VERSION 5.8 ;
BUSBITCHARS "[]" ;
DIVIDERCHAR "/" ;

PROPERTYDEFINITIONS
  MACRO CatenaDesignType STRING ;
END PROPERTYDEFINITIONS

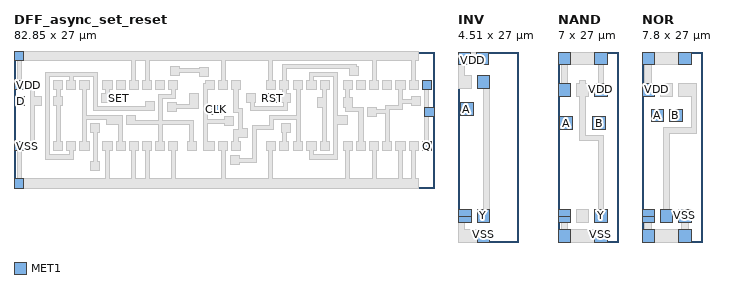
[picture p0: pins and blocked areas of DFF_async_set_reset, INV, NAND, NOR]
MACRO DFF_async_set_reset
  CLASS CORE ;
  ORIGIN -6.4 -6.7 ;
  FOREIGN DFF_async_set_reset 6.4 6.7 ;
  SIZE 82.85 BY 27 ;
  SYMMETRY X Y ;
  SITE CoreSite ;
  PIN VSS
    DIRECTION INOUT ;
    USE GROUND ;
    SHAPE ABUTMENT ;
    PORT
      LAYER MET1 ;
        RECT 6.5 14.01 8.3 15.81 ;
        RECT 6.4 6.7 8.18 8.5 ;
    END
  END VSS
  PIN VDD
    DIRECTION INOUT ;
    USE POWER ;
    SHAPE ABUTMENT ;
    PORT
      LAYER MET1 ;
        RECT 6.5 26.1 8.3 27.9 ;
        RECT 6.4 31.9 8.18 33.7 ;
    END
  END VDD
  PIN SET
    DIRECTION INPUT ;
    USE ANALOG ;
    PORT
      LAYER MET1 ;
        RECT 26.2 23.5 28 25.3 ;
    END
  END SET
  PIN RST
    DIRECTION INPUT ;
    USE ANALOG ;
    PORT
      LAYER MET1 ;
        RECT 56.43 23.5 58.23 25.3 ;
    END
  END RST
  PIN Q
    DIRECTION OUTPUT ;
    USE SIGNAL ;
    PORT
      LAYER MET1 ;
        RECT 87.45 20.85 89.25 22.65 ;
        RECT 86.95 14.01 88.75 15.81 ;
        RECT 86.95 26.1 88.75 27.9 ;
    END
  END Q
  PIN D
    DIRECTION INPUT ;
    USE SIGNAL ;
    PORT
      LAYER MET1 ;
        RECT 6.75 22.95 8.55 24.75 ;
    END
  END D
  PIN CLK
    DIRECTION INPUT ;
    USE CLOCK ;
    PORT
      LAYER MET1 ;
        RECT 45.44 21.21 47.24 23.01 ;
    END
  END CLK
  OBS
    LAYER MET1 ;
      POLYGON 89.25 22.65 88.25 22.65 88.25 26.1 88.75 26.1 88.75 27.9 86.95 27.9 86.95 26.1 87.45 26.1 87.45 15.81 86.95 15.81 86.95 14.01 88.75 14.01 88.75 15.81 88.25 15.81 88.25 20.85 89.25 20.85 ;
      POLYGON 86.65 24.75 84.85 24.75 84.85 24.25 83.06 24.25 83.06 26.1 83.55 26.1 83.55 27.9 81.75 27.9 81.75 26.1 82.26 26.1 82.26 22.98 79.66 22.98 79.66 22.15 78 22.15 78 22.65 76.2 22.65 76.2 20.85 78 20.85 78 21.35 79.66 21.35 79.66 15.81 79.15 15.81 79.15 14.01 80.95 14.01 80.95 15.81 80.46 15.81 80.46 22.18 83.06 22.18 83.06 23.45 84.85 23.45 84.85 22.95 86.65 22.95 ;
      POLYGON 86.2 8.5 85.65 8.5 85.65 14.01 86.15 14.01 86.15 15.81 84.35 15.81 84.35 14.01 84.85 14.01 84.85 8.5 83.05 8.5 83.05 14.01 83.55 14.01 83.55 15.81 81.75 15.81 81.75 14.01 82.25 14.01 82.25 8.5 77.85 8.5 77.85 14.01 78.35 14.01 78.35 15.81 76.55 15.81 76.55 14.01 77.05 14.01 77.05 8.5 72.65 8.5 72.65 14.01 73.15 14.01 73.15 15.81 71.35 15.81 71.35 14.01 71.85 14.01 71.85 8.5 57.48 8.5 57.48 14.01 57.98 14.01 57.98 15.81 56.18 15.81 56.18 14.01 56.68 14.01 56.68 8.5 48.12 8.5 48.12 14.01 48.49 14.01 48.49 15.81 46.69 15.81 46.69 14.01 47.32 14.01 47.32 8.5 38.25 8.5 38.25 14.01 38.75 14.01 38.75 15.81 36.95 15.81 36.95 14.01 37.45 14.01 37.45 8.5 33.05 8.5 33.05 14.01 33.55 14.01 33.55 15.81 31.75 15.81 31.75 14.01 32.25 14.01 32.25 8.5 30.45 8.5 30.45 14.01 30.95 14.01 30.95 15.81 29.15 15.81 29.15 14.01 29.65 14.01 29.65 8.5 25.25 8.5 25.25 14.01 25.75 14.01 25.75 15.81 23.95 15.81 23.95 14.01 24.45 14.01 24.45 8.5 7.8 8.5 7.8 14.01 8.3 14.01 8.3 15.81 6.5 15.81 6.5 14.01 7 14.01 7 8.5 6.4 8.5 6.4 6.7 86.2 6.7 ;
      POLYGON 86.2 33.7 6.4 33.7 6.4 31.9 7 31.9 7 27.9 6.5 27.9 6.5 26.1 8.3 26.1 8.3 27.9 7.8 27.9 7.8 31.9 29.65 31.9 29.65 27.9 29.15 27.9 29.15 26.1 30.95 26.1 30.95 27.9 30.45 27.9 30.45 31.9 32.25 31.9 32.25 27.9 31.75 27.9 31.75 26.1 33.55 26.1 33.55 27.9 33.05 27.9 33.05 31.9 47.24 31.9 47.24 27.9 46.69 27.9 46.69 26.1 48.49 26.1 48.49 27.9 48.04 27.9 48.04 31.9 56.68 31.9 56.68 27.9 56.18 27.9 56.18 26.1 57.98 26.1 57.98 27.9 57.48 27.9 57.48 31.9 77.05 31.9 77.05 27.9 76.55 27.9 76.55 26.1 78.35 26.1 78.35 27.9 77.85 27.9 77.85 31.9 84.85 31.9 84.85 27.9 84.35 27.9 84.35 26.1 86.15 26.1 86.15 27.9 85.65 27.9 85.65 31.9 86.2 31.9 ;
      RECT 79.15 26.1 80.95 27.9 ;
      POLYGON 75.75 15.81 75.25 15.81 75.25 22.67 73.15 22.67 73.15 24.47 72.65 24.47 72.65 26.1 73.15 26.1 73.15 27.9 71.35 27.9 71.35 26.1 71.85 26.1 71.85 24.47 71.35 24.47 71.35 22.67 71.85 22.67 71.85 21.87 74.45 21.87 74.45 15.81 73.95 15.81 73.95 14.01 75.75 14.01 ;
      RECT 73.95 26.1 75.75 27.9 ;
      POLYGON 74.45 30.69 73.95 30.69 73.95 31.1 59.28 31.1 59.28 27.9 58.78 27.9 58.78 26.1 59.28 26.1 59.28 25.3 59.13 25.3 59.13 23.5 59.63 23.5 59.63 22.7 53.86 22.7 53.86 23.5 54.11 23.5 54.11 25.3 52.31 25.3 52.31 23.5 53.06 23.5 53.06 21.9 60.43 21.9 60.43 23.5 60.93 23.5 60.93 25.3 60.08 25.3 60.08 26.1 60.58 26.1 60.58 27.9 60.08 27.9 60.08 30.3 72.65 30.3 72.65 28.89 74.45 28.89 ;
      POLYGON 72.15 21.07 70.18 21.07 70.18 29.5 64.68 29.5 64.68 27.9 64.18 27.9 64.18 26.1 65.98 26.1 65.98 27.9 65.48 27.9 65.48 28.7 69.38 28.7 69.38 13.21 65.48 13.21 65.48 14.01 65.98 14.01 65.98 15.81 64.18 15.81 64.18 14.01 64.68 14.01 64.68 12.41 70.18 12.41 70.18 19.27 72.15 19.27 ;
      POLYGON 68.58 15.81 68.08 15.81 68.08 26.1 68.58 26.1 68.58 27.9 66.78 27.9 66.78 26.1 67.28 26.1 67.28 24.47 66.28 24.47 66.28 22.67 67.28 22.67 67.28 15.81 66.78 15.81 66.78 14.01 68.58 14.01 ;
      POLYGON 63.38 15.81 62.88 15.81 62.88 26.1 63.38 26.1 63.38 27.9 61.58 27.9 61.58 26.1 62.08 26.1 62.08 21.1 56.73 21.1 56.73 19 53.46 19 53.46 12.48 50.96 12.48 50.96 13.09 49.16 13.09 49.16 11.29 50.96 11.29 50.96 11.68 54.26 11.68 54.26 18.2 57.53 18.2 57.53 20.3 62.08 20.3 62.08 15.81 61.58 15.81 61.58 14.01 63.38 14.01 ;
      POLYGON 60.93 19.5 59.13 19.5 59.13 17.7 59.28 17.7 59.28 15.81 58.78 15.81 58.78 14.01 60.58 14.01 60.58 15.81 60.08 15.81 60.08 17.7 60.93 17.7 ;
      RECT 56.43 23.5 58.23 25.3 ;
      POLYGON 52.39 18.45 51.39 18.45 51.39 22.39 50.59 22.39 50.59 26.1 51.09 26.1 51.09 27.9 49.29 27.9 49.29 26.1 49.79 26.1 49.79 21.59 50.59 21.59 50.59 18.17 49.79 18.17 49.79 15.81 49.29 15.81 49.29 14.01 51.09 14.01 51.09 15.81 50.59 15.81 50.59 16.65 52.39 16.65 ;
      POLYGON 49.79 20.77 47.99 20.77 47.99 20.26 44.64 20.26 44.64 26.1 45.89 26.1 45.89 27.9 44.09 27.9 44.09 27.4 43.84 27.4 43.84 14.01 45.89 14.01 45.89 15.81 44.64 15.81 44.64 19.46 47.99 19.46 47.99 18.97 49.79 18.97 ;
      RECT 45.44 21.21 47.24 23.01 ;
      POLYGON 44.81 30.5 43.01 30.5 43.01 30.19 39.11 30.19 39.11 30.69 37.31 30.69 37.31 28.89 39.11 28.89 39.11 29.39 43.01 29.39 43.01 28.7 44.81 28.7 ;
      POLYGON 42.85 25.3 41.05 25.3 41.05 23.1 38.5 23.1 38.5 23.6 36.7 23.6 36.7 21.8 38.5 21.8 38.5 22.3 42.85 22.3 ;
      POLYGON 42.35 15.9 41.85 15.9 41.85 20.08 35.65 20.08 35.65 24.4 38.25 24.4 38.25 26.1 38.75 26.1 38.75 27.9 36.95 27.9 36.95 26.1 37.45 26.1 37.45 25.2 34.85 25.2 34.85 20.08 30.45 20.08 30.45 21.09 28.65 21.09 28.65 19.29 29.62 19.29 29.62 19.28 34.85 19.28 34.85 15.81 34.35 15.81 34.35 14.01 36.15 14.01 36.15 15.81 35.65 15.81 35.65 19.28 41.05 19.28 41.05 15.9 40.55 15.9 40.55 14.1 42.35 14.1 ;
      RECT 34.35 26.1 36.15 27.9 ;
      POLYGON 34.05 23.69 32.25 23.69 32.25 22.69 22.8 22.69 22.8 29.5 12.6 29.5 12.6 12.41 18.1 12.41 18.1 14.01 18.6 14.01 18.6 15.81 16.8 15.81 16.8 14.01 17.3 14.01 17.3 13.21 13.4 13.21 13.4 28.7 17.3 28.7 17.3 27.9 16.8 27.9 16.8 26.1 18.6 26.1 18.6 27.9 18.1 27.9 18.1 28.7 22 28.7 22 21.89 34.05 21.89 ;
      POLYGON 28.35 15.81 27.85 15.81 27.85 21.09 20.7 21.09 20.7 26.1 21.2 26.1 21.2 27.9 19.4 27.9 19.4 26.1 19.9 26.1 19.9 15.81 19.4 15.81 19.4 14.01 21.2 14.01 21.2 15.81 20.7 15.81 20.7 20.29 24.65 20.29 24.65 19.29 27.05 19.29 27.05 15.81 26.55 15.81 26.55 14.01 28.35 14.01 ;
      RECT 26.55 26.1 28.35 27.9 ;
      RECT 26.2 23.5 28 25.3 ;
      POLYGON 25.75 27.9 23.95 27.9 23.95 26.1 24.45 26.1 24.45 25.3 23.6 25.3 23.6 23.5 25.4 23.5 25.4 25.3 25.25 25.3 25.25 26.1 25.75 26.1 ;
      POLYGON 23.3 12.01 22.8 12.01 22.8 17.68 23.3 17.68 23.3 19.48 21.5 19.48 21.5 17.68 22 17.68 22 12.01 21.5 12.01 21.5 10.21 23.3 10.21 ;
      POLYGON 16 15.81 15.5 15.81 15.5 22.95 16 22.95 16 24.75 15.5 24.75 15.5 26.1 16 26.1 16 27.9 14.2 27.9 14.2 26.1 14.7 26.1 14.7 24.75 14.2 24.75 14.2 22.95 14.7 22.95 14.7 15.81 14.2 15.81 14.2 14.01 16 14.01 ;
      POLYGON 11.8 24.75 10.4 24.75 10.4 26.1 10.9 26.1 10.9 27.9 9.1 27.9 9.1 26.1 9.6 26.1 9.6 15.81 9.1 15.81 9.1 14.01 10.9 14.01 10.9 15.81 10.4 15.81 10.4 22.95 11.8 22.95 ;
      RECT 6.75 22.95 8.55 24.75 ;
  END
  PROPERTY CatenaDesignType "deviceLevel" ;
END DFF_async_set_reset

MACRO INV
  CLASS CORE ;
  ORIGIN -0.4 15.73 ;
  FOREIGN INV 0.4 -15.73 ;
  SIZE 4.51 BY 27 ;
  SYMMETRY X Y ;
  SITE CoreSite ;
  PIN Y
    DIRECTION OUTPUT ;
    USE SIGNAL ;
    PORT
      LAYER MET1 ;
        RECT 3.1 -12.91 4.9 -11.11 ;
        RECT 3.1 6.1 4.9 7.9 ;
    END
  END Y
  PIN VSS
    DIRECTION INOUT ;
    USE GROUND ;
    SHAPE ABUTMENT ;
    PORT
      LAYER MET1 ;
        RECT 3.13 -15.73 4.91 -13.93 ;
        RECT 0.5 -12.13 2.3 -11.11 ;
        RECT 0.5 -12.91 2.28 -11.11 ;
    END
  END VSS
  PIN VDD
    DIRECTION INOUT ;
    USE POWER ;
    SHAPE ABUTMENT ;
    PORT
      LAYER MET1 ;
        RECT 3.02 9.47 4.8 11.27 ;
        RECT 0.4 9.47 2.18 11.27 ;
    END
  END VDD
  PIN A
    DIRECTION INPUT ;
    USE SIGNAL ;
    PORT
      LAYER MET1 ;
        RECT 0.75 2.27 2.55 4.07 ;
    END
  END A
  OBS
    LAYER MET1 ;
      POLYGON 4.91 -13.93 1.31 -13.93 1.31 -12.91 2.3 -12.91 2.3 -11.11 0.5 -11.11 0.5 -12.91 0.51 -12.91 0.51 -15.73 4.91 -15.73 ;
      POLYGON 4.9 7.9 3.1 7.9 3.1 6.1 4 6.1 4 -11.11 3.1 -11.11 3.1 -12.91 4.9 -12.91 ;
      POLYGON 4.8 11.27 0.4 11.27 0.4 9.47 0.5 9.47 0.5 6.1 2.3 6.1 2.3 7.9 1.3 7.9 1.3 9.47 4.8 9.47 ;
      RECT 0.75 2.27 2.55 4.07 ;
  END
  PROPERTY CatenaDesignType "deviceLevel" ;
END INV

MACRO NAND
  CLASS CORE ;
  ORIGIN -0.5 9.17 ;
  FOREIGN NAND 0.5 -9.17 ;
  SIZE 7 BY 27 ;
  SYMMETRY X Y ;
  SITE CoreSite ;
  PIN A
    DIRECTION INPUT ;
    USE SIGNAL ;
    PORT
      LAYER MET1 ;
        RECT 0.75 6.8 2.55 8.6 ;
    END
  END A
  PIN VSS
    DIRECTION INOUT ;
    USE GROUND ;
    SHAPE ABUTMENT ;
    PORT
      LAYER MET1 ;
        RECT 5.72 -9.17 7.5 -7.37 ;
        RECT 0.5 -5.57 2.3 -4.57 ;
        RECT 0.5 -6.37 2.28 -4.57 ;
        RECT 0.5 -9.17 2.28 -7.37 ;
    END
  END VSS
  PIN Y
    DIRECTION OUTPUT ;
    USE SIGNAL ;
    PORT
      LAYER MET1 ;
        RECT 5.7 -6.37 7.5 -4.57 ;
    END
  END Y
  PIN B
    DIRECTION INPUT ;
    USE SIGNAL ;
    PORT
      LAYER MET1 ;
        RECT 5.45 6.8 7.25 8.6 ;
    END
  END B
  PIN VDD
    DIRECTION INOUT ;
    USE POWER ;
    SHAPE ABUTMENT ;
    PORT
      LAYER MET1 ;
        RECT 5.7 11.55 7.5 13.35 ;
        RECT 5.72 16.03 7.5 17.83 ;
        RECT 0.5 11.55 2.3 13.35 ;
        RECT 0.5 16.03 2.28 17.83 ;
    END
  END VDD
  OBS
    LAYER MET1 ;
      POLYGON 7.5 -7.37 1.8 -7.37 1.8 -6.37 2.3 -6.37 2.3 -4.57 0.5 -4.57 0.5 -6.37 1 -6.37 1 -7.37 0.5 -7.37 0.5 -9.17 7.5 -9.17 ;
      POLYGON 7.5 -4.57 7 -4.57 7 6 4.4 6 4.4 11.55 4.9 11.55 4.9 13.35 4.4 13.35 4.4 13.75 3.6 13.75 3.6 13.35 3.1 13.35 3.1 11.55 3.6 11.55 3.6 5.2 6.2 5.2 6.2 -4.57 5.7 -4.57 5.7 -6.37 7.5 -6.37 ;
      POLYGON 7.5 13.35 7 13.35 7 16.03 7.5 16.03 7.5 17.83 0.5 17.83 0.5 16.03 1 16.03 1 13.35 0.5 13.35 0.5 11.55 2.3 11.55 2.3 13.35 1.8 13.35 1.8 16.03 6.2 16.03 6.2 13.35 5.7 13.35 5.7 11.55 7.5 11.55 ;
      RECT 5.45 6.8 7.25 8.6 ;
      RECT 3.1 -6.37 4.9 -4.57 ;
      RECT 0.75 6.8 2.55 8.6 ;
  END
  PROPERTY CatenaDesignType "deviceLevel" ;
END NAND

MACRO NOR
  CLASS CORE ;
  ORIGIN -0.5 10.86 ;
  FOREIGN NOR 0.5 -10.86 ;
  SIZE 7.8 BY 27 ;
  SYMMETRY X Y ;
  SITE CoreSite ;
  PIN Y
    DIRECTION OUTPUT ;
    USE SIGNAL ;
    PORT
      LAYER MET1 ;
        RECT 3.1 -8.06 4.9 -6.26 ;
    END
  END Y
  PIN VSS
    DIRECTION INOUT ;
    USE GROUND ;
    SHAPE ABUTMENT ;
    PORT
      LAYER MET1 ;
        RECT 5.72 -10.86 7.5 -9.06 ;
        RECT 5.7 -7.26 7.5 -6.26 ;
        RECT 5.72 -8.06 7.5 -6.26 ;
        RECT 0.5 -7.26 2.3 -6.26 ;
        RECT 0.5 -8.06 2.28 -6.26 ;
        RECT 0.5 -10.86 2.28 -9.06 ;
    END
  END VSS
  PIN VDD
    DIRECTION INOUT ;
    USE POWER ;
    SHAPE ABUTMENT ;
    PORT
      LAYER MET1 ;
        RECT 5.72 14.34 7.5 16.14 ;
        RECT 0.5 9.86 2.3 11.66 ;
        RECT 0.5 14.34 2.28 16.14 ;
    END
  END VDD
  PIN B
    DIRECTION INPUT ;
    USE SIGNAL ;
    PORT
      LAYER MET1 ;
        RECT 4.4 6.21 6.2 8.01 ;
    END
  END B
  PIN A
    DIRECTION INPUT ;
    USE SIGNAL ;
    PORT
      LAYER MET1 ;
        RECT 1.8 6.21 3.6 8.01 ;
    END
  END A
  OBS
    LAYER MET1 ;
      POLYGON 8.3 11.66 5.7 11.66 5.7 9.86 7.5 9.86 7.5 5.37 3.6 5.37 3.6 -6.26 3.1 -6.26 3.1 -8.06 4.9 -8.06 4.9 -6.26 4.4 -6.26 4.4 4.57 8.3 4.57 ;
      POLYGON 7.5 -9.06 7.1 -9.06 7.1 -8.06 7.5 -8.06 7.5 -6.26 5.7 -6.26 5.7 -8.06 6.1 -8.06 6.1 -9.06 1.9 -9.06 1.9 -8.06 2.3 -8.06 2.3 -6.26 0.5 -6.26 0.5 -8.06 0.9 -8.06 0.9 -9.06 0.5 -9.06 0.5 -10.86 7.5 -10.86 ;
      POLYGON 7.5 16.14 0.5 16.14 0.5 14.34 0.9 14.34 0.9 11.66 0.5 11.66 0.5 9.86 2.3 9.86 2.3 11.66 1.9 11.66 1.9 14.34 7.5 14.34 ;
      RECT 4.4 6.21 6.2 8.01 ;
      RECT 3.1 9.86 4.9 11.66 ;
      RECT 1.8 6.21 3.6 8.01 ;
  END
  PROPERTY CatenaDesignType "deviceLevel" ;
END NOR

END LIBRARY
